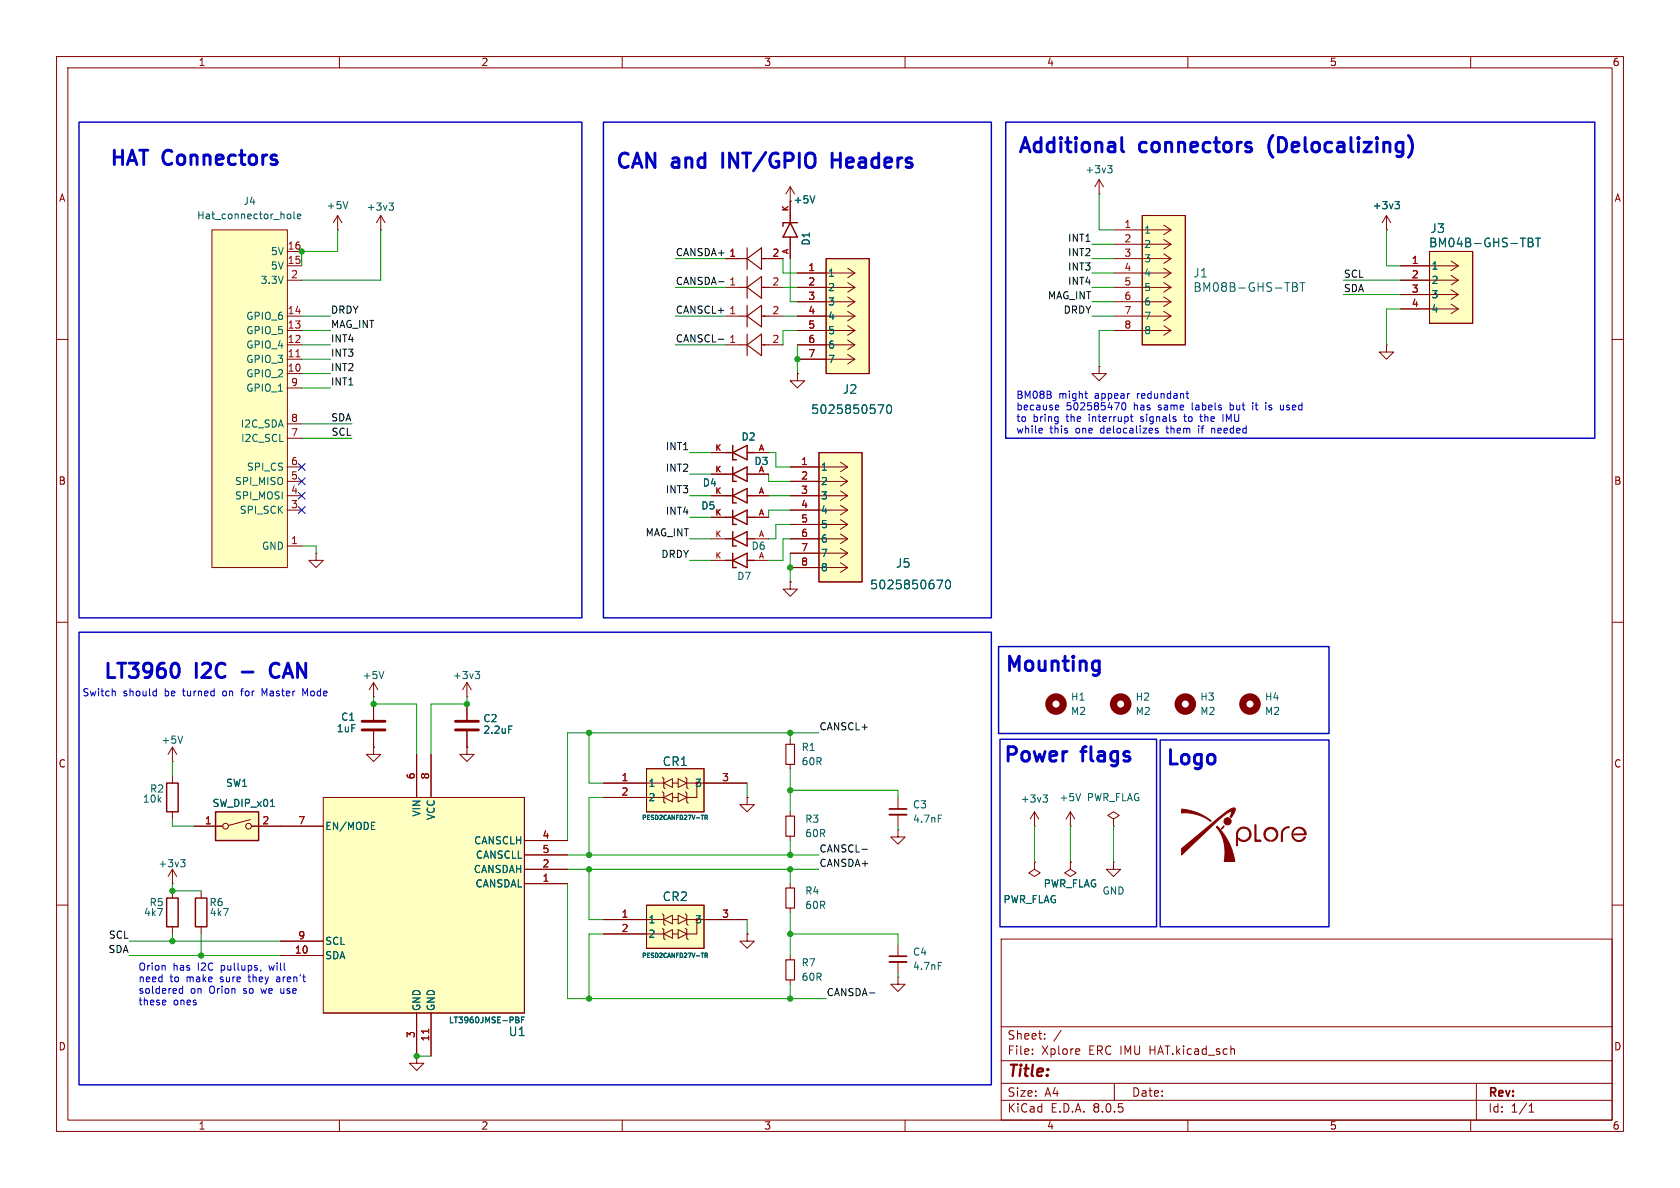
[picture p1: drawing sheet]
<svg xmlns="http://www.w3.org/2000/svg" width="297mm" height="210mm" viewBox="0 0 297 210" stroke-linecap="round" stroke-linejoin="round" font-family="sans-serif">
<defs><g id="words">
<g font-size="3.5" fill="#0000c2">
<text x="19.1" y="30">HAT Connectors</text>
<text x="179.8" y="27.2">Additional</text>
<text x="201.7" y="27.2">connectors</text>
<text x="225.4" y="27.2">(Delocalizing)</text>
<text x="108.5" y="30.5">CAN</text>
<text x="118.8" y="30.5">and</text>
<text x="128.7" y="30.5">INT/GPIO</text>
<text x="149" y="30.5">Headers</text>
<text x="177.5" y="118.9">Mounting</text>
<text x="18" y="120.7">LT3960</text>
<text x="34.6" y="120.7">I2C</text>
<text x="49.8" y="120.7">CAN</text>
<text x="177.3" y="134.9">Power</text>
<text x="191.5" y="134.9">flags</text>
<text x="206" y="135.4">Logo</text>
</g>
<text font-size="2.8" fill="#840000" x="178" y="190.9">Title:</text>
<g font-size="2.1" fill="#006464">
<text x="252.8" y="41.4">J3</text>
<text x="252.5" y="43.9">BM04B-GHS-TBT</text>
<text x="210.9" y="49.3">J1</text>
<text x="210.9" y="51.8">BM08B-GHS-TBT</text>
<text x="148.9" y="69.8">J2</text>
<text x="143.3" y="73.4">5025850570</text>
<text x="158.3" y="100.6">J5</text>
<text x="153.7" y="104.4">5025850670</text>
<text x="117.1" y="135.6">CR1</text>
<text x="117.1" y="159.5">CR2</text>
<text x="89.8" y="183.4">U1</text>
</g>
<g font-size="2.1" fill="#840000">
<text x="178" y="184">Sheet:</text>
<text x="178" y="186.7">File:</text>
<text x="184.1" y="186.7">Xplore</text>
<text x="192.5" y="186.7">ERC IMU</text>
<text x="203.5" y="186.7">HAT.kicad_sch</text>
<text x="178" y="196.9">KiCad</text>
<text x="178" y="194.1">Size:</text>
<text x="184.7" y="194.1">A4</text>
<text x="185.7" y="196.9">E.D.A.</text>
<text x="193.3" y="196.9">8.0.5</text>
<text x="200" y="194.1">Date:</text>
<text x="263" y="194.3">Rev:</text>
<text x="263" y="196.9">Id:</text>
<text x="267.1" y="196.9">1/1</text>
</g>
<g font-size="1.8" fill="#840000">
<text x="35" y="11.9">1</text>
<text x="85" y="11.9">2</text>
<text x="135" y="11.9">3</text>
<text x="185" y="11.9">4</text>
<text x="235" y="11.9">5</text>
<text x="285" y="11.9">6</text>
<text x="10.3" y="35.9">A</text>
<text x="285.3" y="35.9">A</text>
<text x="140.2" y="36.2">+5V</text>
<text x="10.3" y="85.9">B</text>
<text x="285.3" y="85.9">B</text>
<text x="10.3" y="135.9">C</text>
<text x="285.3" y="135.9">C</text>
<text x="10.3" y="185.9">D</text>
<text x="285.3" y="185.9">D</text>
<text x="35" y="199.9">1</text>
<text x="85" y="199.9">2</text>
<text x="135" y="199.9">3</text>
<text x="185" y="199.9">4</text>
<text x="235" y="199.9">5</text>
<text x="285" y="199.9">6</text>
</g>
<g font-size="1.8" fill="#006464">
<text x="191.8" y="30.8">+3v3</text>
<text x="34.7" y="39">Hat_connector_hole</text>
<text x="42.9" y="36.4">J4</text>
<text x="57.7" y="37.2">+5V</text>
<text x="64.7" y="37.4">+3v3</text>
<text x="202.2" y="41.5">1</text>
<text x="242.6" y="37.2">+3v3</text>
<text x="47.8" y="47.9">5V</text>
<text x="47.8" y="45.3">5V</text>
<text x="143.4" y="43.5" transform="rotate(-90 143.4 43.5)">D1</text>
<text x="202.2" y="44">2</text>
<text x="202.2" y="46.6">3</text>
<text x="253" y="47.9">1</text>
<text x="46" y="50.4">3.3V</text>
<text x="146.3" y="49.1">1</text>
<text x="146.3" y="51.7">2</text>
<text x="202.2" y="49.1">4</text>
<text x="202.2" y="51.7">5</text>
<text x="253" y="50.4">2</text>
<text x="253" y="52.9">3</text>
<text x="43.4" y="59.3">GPIO_5</text>
<text x="43.4" y="56.7">GPIO_6</text>
<text x="146.3" y="54.2">3</text>
<text x="146.3" y="56.7">4</text>
<text x="146.3" y="59.3">5</text>
<text x="202.2" y="54.2">6</text>
<text x="202.2" y="56.7">7</text>
<text x="202.2" y="59.3">8</text>
<text x="253" y="55.5">4</text>
<text x="43.4" y="64.4">GPIO_3</text>
<text x="43.4" y="61.8">GPIO_4</text>
<text x="146.3" y="61.8">6</text>
<text x="146.3" y="64.4">7</text>
<text x="43.4" y="66.9">GPIO_2</text>
<text x="43.4" y="69.4">GPIO_1</text>
<text x="42.5" y="75.8">I2C_SDA</text>
<text x="42.5" y="78.3">I2C_SCL</text>
<text x="43.6" y="83.4">SPI_CS</text>
<text x="131" y="78.1">D2</text>
<text x="133.3" y="82.4">D3</text>
<text x="145" y="83.4">1</text>
<text x="41.4" y="88.5">SPI_MOSI</text>
<text x="41.4" y="86">SPI_MISO</text>
<text x="124.1" y="86.2">D4</text>
<text x="145" y="86">2</text>
<text x="145" y="88.5">3</text>
<text x="42.3" y="91">SPI_SCK</text>
<text x="123.9" y="90.3">D5</text>
<text x="145" y="91">4</text>
<text x="145" y="93.6">5</text>
<text x="46.2" y="97.4">GND</text>
<text x="132.8" y="97.4">D6</text>
<text x="145" y="96.1">6</text>
<text x="145" y="98.7">7</text>
<text x="145" y="101.2">8</text>
<text x="130.2" y="102.7">D7</text>
<text x="64" y="120.2">+5V</text>
<text x="80" y="120.2">+3v3</text>
<text x="189.2" y="124.1">H1</text>
<text x="200.7" y="124.1">H2</text>
<text x="212.1" y="124.1">H3</text>
<text x="223.5" y="124.1">H4</text>
<text x="28.4" y="131.7">+5V</text>
<text x="59.4" y="129.6">1uF</text>
<text x="60.2" y="127.6">C1</text>
<text x="85.4" y="127.9">C2</text>
<text x="85.4" y="129.9">2.2uF</text>
<text x="189.2" y="126.6">M2</text>
<text x="200.7" y="126.6">M2</text>
<text x="212.1" y="126.6">M2</text>
<text x="223.5" y="126.6">M2</text>
<text x="141.6" y="132.9">R1</text>
<text x="141.6" y="135.5">60R</text>
<text x="25.2" y="142.1">10k</text>
<text x="26.4" y="140.3">R2</text>
<text x="37.5" y="142.8">SW_DIP_x01</text>
<text x="39.9" y="139.3">SW1</text>
<text x="114.6" y="139.3">1</text>
<text x="114.6" y="141.8">2</text>
<text x="122.8" y="139.3">3</text>
<text x="161.3" y="143.1">C3</text>
<text x="180.3" y="142.1">+3v3</text>
<text x="187.2" y="141.8">+5V</text>
<text x="192" y="141.8">PWR_FLAG</text>
<text x="57.4" y="146.9">EN/MODE</text>
<text x="74.5" y="144.5" transform="rotate(-90 74.5 144.5)">VIN</text>
<text x="77.1" y="145.1" transform="rotate(-90 77.1 145.1)">VCC</text>
<text x="83.7" y="149.5">CANSCLH</text>
<text x="142.2" y="145.6">R3</text>
<text x="142.2" y="148.2">60R</text>
<text x="161.3" y="145.6">4.7nF</text>
<text x="27.9" y="153.5">+3v3</text>
<text x="83.7" y="154.5">CANSDAH</text>
<text x="84" y="152">CANSCLL</text>
<text x="26.3" y="160.4">R5</text>
<text x="36.9" y="160.4">R6</text>
<text x="84" y="157.1">CANSDAL</text>
<text x="142.2" y="158.3">R4</text>
<text x="142.2" y="160.9">60R</text>
<text x="177.3" y="159.9">PWR_FLAG</text>
<text x="184.4" y="157.1">PWR_FLAG</text>
<text x="194.8" y="158.3">GND</text>
<text x="25.4" y="162.2">4k7</text>
<text x="37" y="162.2">4k7</text>
<text x="57.4" y="167.2">SCL</text>
<text x="114.6" y="163.4">1</text>
<text x="114.6" y="166">2</text>
<text x="122.8" y="163.4">3</text>
<text x="57.4" y="169.8">SDA</text>
<text x="141.6" y="171">R7</text>
<text x="141.6" y="173.6">60R</text>
<text x="161.3" y="169.1">C4</text>
<text x="161.3" y="171.7">4.7nF</text>
<text x="74.5" y="178.8" transform="rotate(-90 74.5 178.8)">GND</text>
<text x="77.1" y="178.8" transform="rotate(-90 77.1 178.8)">GND</text>
</g>
<g font-size="1.8" fill="#a90000">
<text x="198.7" y="40.4">1</text>
<text x="50.8" y="46.7">15</text>
<text x="50.8" y="44.2">16</text>
<text x="128.8" y="45.5">1</text>
<text x="136.5" y="45.5">2</text>
<text x="198.7" y="42.9">2</text>
<text x="198.7" y="45.5">3</text>
<text x="249.5" y="46.7">1</text>
<text x="51.4" y="49.3">2</text>
<text x="128.8" y="50.5">1</text>
<text x="136.5" y="50.5">2</text>
<text x="142.8" y="48">1</text>
<text x="142.8" y="50.5">2</text>
<text x="142.8" y="53.1">3</text>
<text x="198.7" y="48">4</text>
<text x="198.7" y="50.5">5</text>
<text x="198.7" y="53.1">6</text>
<text x="249.5" y="49.3">2</text>
<text x="249.5" y="51.8">3</text>
<text x="50.8" y="58.2">13</text>
<text x="50.8" y="55.6">14</text>
<text x="128.8" y="55.6">1</text>
<text x="136.5" y="55.6">2</text>
<text x="142.8" y="55.6">4</text>
<text x="142.8" y="58.2">5</text>
<text x="198.7" y="55.6">7</text>
<text x="198.7" y="58.2">8</text>
<text x="249.5" y="54.4">4</text>
<text x="50.8" y="65.8">10</text>
<text x="50.8" y="63.2">11</text>
<text x="50.8" y="60.7">12</text>
<text x="128.8" y="60.7">1</text>
<text x="136.5" y="60.7">2</text>
<text x="142.8" y="60.7">6</text>
<text x="142.8" y="63.2">7</text>
<text x="51.4" y="68.3">9</text>
<text x="51.4" y="77.2">7</text>
<text x="51.4" y="74.7">8</text>
<text x="51.4" y="82.3">6</text>
<text x="141.5" y="82.3">1</text>
<text x="51.4" y="89.9">3</text>
<text x="51.4" y="87.4">4</text>
<text x="51.4" y="84.8">5</text>
<text x="141.5" y="84.8">2</text>
<text x="141.5" y="87.4">3</text>
<text x="141.5" y="89.9">4</text>
<text x="141.5" y="92.5">5</text>
<text x="141.5" y="95">6</text>
<text x="51.4" y="96.3">1</text>
<text x="141.5" y="97.5">7</text>
<text x="141.5" y="100.1">8</text>
<text x="73.4" y="137.9" transform="rotate(-90 73.4 137.9)">6</text>
<text x="75.9" y="137.9" transform="rotate(-90 75.9 137.9)">8</text>
<text x="109.8" y="138.2">1</text>
<text x="109.8" y="140.7">2</text>
<text x="127.6" y="138.2">3</text>
<text x="36.1" y="145.8">1</text>
<text x="46.3" y="145.8">2</text>
<text x="52.6" y="145.8">7</text>
<text x="95.8" y="148.3">4</text>
<text x="95.8" y="156">1</text>
<text x="95.8" y="153.4">2</text>
<text x="95.8" y="150.9">5</text>
<text x="52.6" y="166.1">9</text>
<text x="109.8" y="162.3">1</text>
<text x="109.8" y="164.8">2</text>
<text x="127.6" y="162.3">3</text>
<text x="52" y="168.7">10</text>
<text x="73.4" y="183.6" transform="rotate(-90 73.4 183.6)">3</text>
<text x="75.9" y="184.2" transform="rotate(-90 75.9 184.2)">11</text>
</g>
<g font-size="1.8" fill="#0f0f0f">
<text x="119.4" y="45.4">CANSDA+ 1</text>
<text x="188.7" y="45.4">INT2</text>
<text x="188.7" y="47.9">INT3</text>
<text x="188.7" y="42.8">INT1</text>
<text x="119.4" y="50.5">CANSDA-</text>
<text x="185.2" y="53">MAG_INT</text>
<text x="188.7" y="50.5">INT4</text>
<text x="237.5" y="51.7">SDA</text>
<text x="237.5" y="49.2">SCL</text>
<text x="58.4" y="55.5">DRDY</text>
<text x="58.4" y="58.1">MAG_INT</text>
<text x="119.4" y="55.5">CANSCL+</text>
<text x="187.9" y="55.5">DRDY</text>
<text x="58.4" y="60.6">INT4</text>
<text x="58.4" y="63.2">INT3</text>
<text x="58.4" y="65.7">INT2</text>
<text x="119.4" y="60.6">CANSCL-</text>
<text x="58.4" y="68.2">INT1</text>
<text x="58.5" y="74.6">SDA</text>
<text x="58.5" y="77.1">SCL</text>
<text x="117.6" y="79.7">INT1</text>
<text x="117.6" y="83.5">INT2</text>
<text x="117.6" y="87.3">INT3</text>
<text x="114" y="94.9">MAG_INT</text>
<text x="117.6" y="91.1">INT4</text>
<text x="116.8" y="98.7">DRDY</text>
<text x="144.8" y="129.2">CANSCL+</text>
<text x="144.8" y="153.3">CANSDA+</text>
<text x="144.8" y="150.8">CANSCL-</text>
<text x="19.1" y="166">SCL</text>
<text x="19.1" y="168.6">SDA</text>
<text x="146" y="176.2">CANSDA-</text>
</g>
<g font-size="1.8" fill="#0000c2">
<text x="179.6" y="70.7">BM08B</text>
<text x="187.2" y="70.7">might</text>
<text x="193.7" y="70.7">appear</text>
<text x="201.3" y="70.7">redundant</text>
<text x="179.6" y="72.7">because</text>
<text x="179.6" y="74.8">to</text>
<text x="179.6" y="76.8">while</text>
<text x="182.6" y="74.8">bring</text>
<text x="185.6" y="76.8">this</text>
<text x="188.5" y="72.7">502585470</text>
<text x="188.6" y="74.8">the</text>
<text x="190.3" y="76.8">one</text>
<text x="192.8" y="74.8">interrupt</text>
<text x="194.8" y="76.8">delocalizes</text>
<text x="200.5" y="72.7">has</text>
<text x="202.1" y="74.8">signals</text>
<text x="205" y="72.7">same</text>
<text x="206.7" y="76.8">them</text>
<text x="210" y="74.8">to</text>
<text x="211.2" y="72.7">labels</text>
<text x="212.5" y="76.8">if</text>
<text x="213.1" y="74.8">the</text>
<text x="215" y="76.8">needed</text>
<text x="217.2" y="74.8">IMU</text>
<text x="218.1" y="72.7">but</text>
<text x="222.3" y="72.7">it</text>
<text x="224.8" y="72.7">is</text>
<text x="227.6" y="72.7">used</text>
<text x="14.5" y="123.3">Switch</text>
<text x="21.8" y="123.3">should</text>
<text x="29.2" y="123.3">be</text>
<text x="32.6" y="123.3">turned</text>
<text x="39.8" y="123.3">on</text>
<text x="43.3" y="123.3">for</text>
<text x="47.1" y="123.3">Master</text>
<text x="54.5" y="123.3">Mode</text>
<text x="24.4" y="171.8">Orion</text>
<text x="24.4" y="173.8">need</text>
<text x="30" y="173.8">to</text>
<text x="30.6" y="171.8">has</text>
<text x="33.1" y="173.8">make</text>
<text x="35.1" y="171.8">I2C</text>
<text x="39.2" y="173.8">sure</text>
<text x="39.3" y="171.8">pullups,</text>
<text x="44.4" y="173.8">they</text>
<text x="48.1" y="171.8">will</text>
<text x="49.5" y="173.8">aren't</text>
<text x="24.4" y="175.9">soldered</text>
<text x="24.4" y="177.9">these</text>
<text x="30.6" y="177.9">ones</text>
<text x="33.7" y="175.9">on</text>
<text x="37.1" y="175.9">Orion</text>
<text x="43.3" y="175.9">so</text>
<text x="46.7" y="175.9">we</text>
<text x="50.3" y="175.9">use</text>
</g>
<g font-size="1.4" fill="#a90000">
<text x="139.4" y="37.5" transform="rotate(-90 139.4 37.5)">K</text>
<text x="139.4" y="45" transform="rotate(-90 139.4 45)">A</text>
<text x="126.4" y="79.8">K</text>
<text x="126.4" y="83.6">K</text>
<text x="134.1" y="79.8">A</text>
<text x="134.1" y="83.6">A</text>
<text x="126.4" y="87.4">K</text>
<text x="134.1" y="87.4">A</text>
<text x="126.4" y="91.2">K</text>
<text x="126.4" y="95">K</text>
<text x="134.1" y="91.2">A</text>
<text x="134.1" y="95">A</text>
<text x="126.4" y="98.8">K</text>
<text x="134.1" y="98.8">A</text>
</g>
<text font-size="1.4" fill="#006464" x="79.3" y="181.1">LT3960JMSE-PBF</text>
<g font-size="1.1" fill="#006464">
<text x="113.4" y="145.1">PESD2CANFD27V-TR</text>
<text x="113.4" y="169.5">PESD2CANFD27V-TR</text>
</g>
</g></defs>
<g fill="none" stroke="#840000" stroke-width=".18">
<path d="M10 10h277v190h-277zM12 12h273v186h-273zM60 10v2M110 10v2M160 10v2M210 10v2M260 10v2M10 60h2M285 60h2M10 110h2M285 110h2M10 160h2"/>
<path d="M285 160h2M177 166h108v32h-108zM60 198v2M110 198v2M160 198v2M177 194.5h108M177 191.5h108M177 187.5h108M177 181.5h108M182.5 186.3v.1M182.5 185.5v.1M184.7 183.6v.1"/>
<path d="M184.7 182.8v.1M187.6 182.1l-1.3 2M190.7 185.4l.2 .4-.7 .1M190.8 186.3l-.1 .1M197 191.5v3M210 198v2M218 185.4l.2 .2v.8M260 198v2M261 191.5v6.5M270.3 196.6h.9M270.3 195.5l.4-.4v1.5"/>
</g>
<path d="M38.1 143.5h7.6v5.1h-7.6z" fill="#ffffc2"/>
<g fill="none" stroke="#840000" stroke-width=".18">
<path d="M125.7 87.6h2.6M125.7 91.4h2.6M133.3 87.6h2.6M133.3 91.4h2.6M82.5 123.2h.1M82.5 120.7l-.7 1.2M82.5 120.7v2.5M82.5 120.7l.8 1.2M30.5 157.5v1.3M34.3 146.1h5.1M35.6 157.5v1.3M44.3 144.9l-3.9 1"/>
<path d="M44.4 146.1h5.1M189.2 152.4v1.3l1 .6-1 .6-1-.6 1-.6M189.2 152.4h.1M30.5 163.8v1.3M35.6 163.8v1.3"/>
<circle cx="39.9" cy="146.1" r=".51"/>
<circle cx="43.9" cy="146.1" r=".51"/>
</g>
<path d="M128.3 87.6h1.2M128.3 91.4h1.2M129.5 87.6l2.6-1.2v2.5zM129.5 91.4l2.6-1.2v2.5zM129.5 86.4v2.5h.7M129.5 90.2v2.5h.7M132.1 87.6h1.2M132.1 91.4h1.2M29.5 158.8h2v5h-2zM34.5 158.8h2.1v5h-2.1zM38.1 143.5h7.6v5.1h-7.6z" fill="none" stroke="#840000" stroke-width=".25"/>
<path d="M84 118.7h.8l-.4 .5 .3 .1 .1 .4-.3 .3h-.3M47.8 142.6h.7" fill="none" stroke="#006464" stroke-width=".18"/>
<circle cx="198.1" cy="124.5" r="1.27" fill="none" stroke="#840000" stroke-width="1.3"/>
<path d="M37.5 40.6h13.3v59.7h-13.3z" fill="#ffffc2"/>
<g fill="none" stroke="#840000" stroke-width=".18">
<path d="M59.7 38.1l-.8 1.3M59.7 38.1v2.5M59.7 38.1l.8 1.3M67.3 38.1l-.8 1.3M67.3 38.1v2.5M67.3 38.1l.8 1.3M37.5 40.6h13.3v59.7h-13.3zM50.8 58.4h2.5M50.8 55.9h2.5M50.8 47h2.5M50.8 44.5h2.5M50.8 49.5h2.5"/>
<path d="M59.7 40.6h.1M67.3 40.6h.1M50.8 66h2.5M50.8 63.5h2.5M50.8 61h2.5M50.8 77.5h2.5M50.8 74.9h2.5M50.8 68.6h2.5M245.1 61v1.2h1.3l-1.3 1.3-1.3-1.3h1.3M245.1 61h.1M50.8 96.5h2.5M50.8 90.2h2.5"/>
<path d="M50.8 87.6h2.5M50.8 85.1h2.5M50.8 82.6h2.5M55.9 97.8v1.3h1.2l-1.2 1.2-1.3-1.2h1.3M55.9 97.8h.1M66 132.1v1.3h1.3l-1.3 1.2-1.2-1.2h1.2M66 132.1h.1M66 124.5v2.8M66 129.3v2.8M82.5 132.1v1.3h1.3l-1.3 1.2-1.2-1.2h1.2M82.5 132.1h.1M82.5 124.5v2.8"/>
<path d="M82.5 129.3v2.8M139.7 130.8v.8M139.7 135.1v.8M132.1 141v1.2h1.2l-1.2 1.3-1.3-1.3h1.3M132.1 141h.1M139.7 143.5v.8M139.7 147.8v.8M139.7 156.2v.8M158.7 146.7v1.3h1.3l-1.3 1.2-1.2-1.2h1.2M158.7 146.7h.1M158.7 141v2M158.7 144v2.1"/>
<path d="M182.9 152.4v1.3l1 .6-1 .6-1-.6 1-.6M182.9 152.4h.1M182.9 146.1h.1M182.9 143.5l-.8 1.3M182.9 143.5v2.6M182.9 143.5l.7 1.3M189.2 146.1h.1M189.2 143.5l-.7 1.3M189.2 143.5v2.6M189.2 143.5l.8 1.3M196.8 152.4v1.3h1.3l-1.3 1.2-1.2-1.2h1.2M196.8 152.4h.1"/>
<path d="M196.8 144.8l1.1-.7-1.1-.6-1 .6 1 .7v1.3M196.8 146.1h.1M139.7 160.5v.8M158.7 167v2M158.7 170.1v2M73.7 186.7v1.3h1.2l-1.2 1.2-1.3-1.2h1.3M73.7 186.7h.1"/>
</g>
<path d="M52.3 63.1h.7" fill="none" stroke="#a90000" stroke-width=".18"/>
<path d="M51 37.8l.3 .1 .1 .2v.5l-.4 .1M52 37.4v1.1l.1 .2M52.6 38.3l.6-.2-.1-.2-.3-.1-.2 .2v.6h.5M61.5 35.6l-.4 1.3M68.8 35.9h.7l-.4 .5 .4 .1v.4l-.2 .3h-.4M89.9 128.3h.6M165.9 144.1h.6M184.4 140.5h.8l-.5 .5 .4 .1 .1 .5-.3 .2h-.3M191 140.3l-.4 1.2M165.9 170.1h.6" fill="none" stroke="#006464" stroke-width=".18"/>
<g fill="none" stroke="#840000" stroke-width="1.3">
<circle cx="186.7" cy="124.5" r="1.27"/>
<circle cx="209.5" cy="124.5" r="1.27"/>
<circle cx="221" cy="124.5" r="1.27"/>
</g>
<path d="M64 129h4.1M64 127.5h4.1M80.5 129h4.1M80.5 127.5h4.1" fill="none" stroke="#840000" stroke-width=".51"/>
<g fill="#840000" stroke="#840000" stroke-width=".18">
<path d="M221.8 145.8h.2l.1 2.7h.8v.2h-1z"/>
<path d="M216.3 146l.1 .1-.4 .5-.1-.1z"/>
<path d="M226.9 146.5l.6-.3 .4-.1v.2a1.32 1.32 0 0 0-1.2 1.7v.7h-.2v-.9a1.67 1.67 0 0 1 .4-1.3z"/>
<path d="M215.2 146.1a11.4 11.4 0 0 1 3.1 6.2h-1.9l.1-.2a7.3 7.3 0 0 0-1.5-5.9z"/>
<path d="M208.9 143h.2a9.5 9.5 0 0 1 5 2.1l-.1 .1a7.2 7.2 0 0 0-5.1-1.5z"/>
<path d="M219 146.6a1.28 1.28 0 0 1 1.8 0 1.28 1.28 0 0 1 0 1.8 1.28 1.28 0 0 1-1.8 0v-.3l.2 .2a1.07 1.07 0 0 0 1.6-.3 1.07 1.07 0 0 0-.6-1.5 1.07 1.07 0 0 0-1.4 .9v2.1h-.2v-1.7a1.46 1.46 0 0 1 .4-1.2z"/>
<path d="M223.8 146.6l.8-.4a1.24 1.24 0 0 1 1.3 1.2 1.24 1.24 0 0 1-1.1 1.3v-.2a1.02 1.02 0 0 0 .8-1.5 1.02 1.02 0 0 0-1.7 0 1.02 1.02 0 0 0 .6 1.5v.2a1.24 1.24 0 0 1-1-.8 1.24 1.24 0 0 1 .3-1.3z"/>
<path d="M208.9 150l6.9-5.7 1.7-1.2a.56 .56 0 0 1 .9 0l-.6 1.2a.17 .17 0 0 1-.2 .2 .17 .17 0 0 1-.1-.3l.2-.5a.18 .18 0 0 0 0-.3 .18 .18 0 0 0-.3 .1l-2 1.5-6.5 6.1z"/>
<path d="M228.7 146.6a1.26 1.26 0 0 1 1.5-.3 1.26 1.26 0 0 1 .7 1.3h-2.1l-.1-.2h2a1.06 1.06 0 0 0-1.6-.8 1.06 1.06 0 0 0-.3 1.7 1.06 1.06 0 0 0 1.7-.3h.3a1.26 1.26 0 0 1-1.9 .6 1.26 1.26 0 0 1-.2-2z"/>
<circle cx="217" cy="145.2" r=".63"/>
</g>
<path d="M138.9 131.6h1.6v3.5h-1.6zM138.9 144.3h1.6v3.5h-1.6zM138.9 157h1.6v3.5h-1.6z" fill="none" stroke="#840000" stroke-width=".2"/>
<path d="M157.2 144h3.1M157.2 170.1h3.1" fill="none" stroke="#840000" stroke-width=".33"/>
<path d="M157.2 143h3.1M157.2 169h3.1" fill="none" stroke="#840000" stroke-width=".3"/>
<path d="M252.7 44.5v12.7h7.6v-12.7" fill="none" stroke="#ffffc2" stroke-width=".18"/>
<path d="M252.7 44.5h7.6v12.7h-7.6z" fill="#ffffc2"/>
<g fill="none" stroke="#840000" stroke-width=".18">
<path d="M194.3 34.3h.1M194.3 31.8l-.8 1.2M194.3 31.8v2.5M194.3 31.8l.8 1.2M245.1 38.1l-.8 1.3M245.1 38.1v2.5M245.1 38.1l.8 1.3M245.1 40.6h.1M247.6 54.6h10.2M247.6 52.1h10.2M247.6 49.5h10.2M247.6 47h10.2"/>
<path d="M252.7 44.5h7.6v12.7h-7.6zM256.5 53.8l1.3 .8M256.5 51.2l1.3 .9M256.5 48.7l1.3 .8M256.5 46.1l1.3 .9M257.8 54.6l-1.3 .9M257.8 52.1l-1.3 .8M257.8 49.5l-1.3 .9M257.8 47l-1.3 .8M194.3 64.8v1.2h1.3l-1.3 1.3-1.3-1.3h1.3M194.3 64.8h.1"/>
</g>
<path d="M195.8 29.3h.8l-.4 .5 .3 .1 .1 .4-.2 .3h-.4M246.6 35.6h.8l-.4 .5 .3 .1 .1 .5-.2 .2h-.4M270.2 42.1h.5l.2 .1 .1 .3-.3 .3M270.2 42.8h.5M270.7 42.8a.41 .41 0 0 1 .4 .4 .41 .41 0 0 1-.3 .4h-.6M271.5 42.1h.8M271.9 42.1v1.5" fill="none" stroke="#006464" stroke-width=".18"/>
<path d="M209.5 38.1v22.9h-7.6" fill="none" stroke="#ffffc2" stroke-width=".18"/>
<path d="M201.9 38.1h7.6v22.9h-7.6z" fill="#ffffc2"/>
<g fill="none" stroke="#840000" stroke-width=".18">
<path d="M201.9 38.1h7.6v22.9h-7.6zM205.7 39.8l1.3 .8M196.8 58.4h10.2M196.8 55.9h10.2M196.8 53.3h10.2M196.8 50.8h10.2M196.8 48.3h10.2M196.8 45.7h10.2M196.8 43.2h10.2M196.8 40.6h10.2M205.7 57.6l1.3 .8M205.7 55l1.3 .9"/>
<path d="M205.7 52.5l1.3 .8M205.7 50l1.3 .8M205.7 47.4l1.3 .9M205.7 44.9l1.3 .8M205.7 42.3l1.3 .9M207 58.4l-1.3 .9M207 55.9l-1.3 .8M207 53.3l-1.3 .9M207 50.8l-1.3 .8M207 48.3l-1.3 .8M207 45.7l-1.3 .9M207 43.2l-1.3 .8"/>
<path d="M207 40.6l-1.3 .9M141 66v1.3h1.2l-1.2 1.3-1.3-1.3h1.3M141 66h.1"/>
</g>
<path d="M228.5 50h.5l.2 .1 .1 .3-.3 .3M228.5 50.7h.5M229 50.7a.41 .41 0 0 1 .4 .4 .41 .41 0 0 1-.3 .4h-.6M229.8 50h.9M230.3 50v1.5" fill="none" stroke="#006464" stroke-width=".18"/>
<path d="M153.7 45.7v20.3" fill="none" stroke="#ffffc2" stroke-width=".18"/>
<path d="M146 45.7h7.7v20.3h-7.7z" fill="#ffffc2"/>
<g fill="none" stroke="#840000" stroke-width=".18">
<path d="M139.7 33l-.8 1.3M139.7 33v5.1M139.7 33l.8 1.3M128.3 55.9h2.5M128.3 50.8h2.5M128.3 45.7h2.5M135.9 55.9h2.5M135.9 50.8h2.5M135.9 45.7h2.5M139.7 43.2v2.5M141 58.4h10.1M141 55.9h10.1"/>
<path d="M141 53.3h10.1M141 50.8h10.1M141 48.3h10.1M146 45.7h7.7v20.3h-7.7zM149.9 57.6l1.2 .8M149.9 55l1.2 .9M149.9 52.5l1.2 .8M149.9 50l1.2 .8M149.9 47.4l1.2 .9M151.1 58.4l-1.2 .9M151.1 55.9l-1.2 .8M151.1 53.3l-1.2 .9"/>
<path d="M151.1 50.8l-1.2 .8M151.1 48.3l-1.2 .8M128.3 61h2.5M135.9 61h2.5M141 63.5h10.1M141 61h10.1M149.9 62.7l1.2 .8M149.9 60.1l1.2 .9M151.1 63.5l-1.2 .8M151.1 61l-1.2 .8M139.7 168.9v.8M139.7 173.2v.8"/>
<path d="M158.7 172.7v1.3h1.3l-1.3 1.3-1.2-1.3h1.2M158.7 172.7h.1"/>
</g>
<path d="M144.1 34.6l-.5 1.3M155.2 71.6h1l-.6 1.5M157 71.6h.1a.83 .83 0 0 1 .6 .6 .83 .83 0 0 1-.3 .8l-.1 .1a.83 .83 0 0 1-.6-.6 .83 .83 0 0 1 .3-.9z" fill="none" stroke="#006464" stroke-width=".18"/>
<path d="M139.7 38.1v1.3M139.7 39.4l1.3 2.5h-2.6zM141 39.4h-2.6v.6M139.7 41.9v1.3" fill="none" stroke="#840000" stroke-width=".25"/>
<g fill="none" stroke="#840000" stroke-width=".2">
<path d="M130.8 45.7h1.3M130.8 50.8h1.3M130.8 55.9h1.3M132.1 45.7l2.5-1.9v3.8zM132.1 50.8l2.5-1.9v3.8zM132.1 55.9l2.5-1.9v3.8zM132.1 43.8v3.8M132.1 48.9v3.8M132.1 54v3.8M132.1 59.1v3.8M134.6 45.7h1.3M134.6 50.8h1.3"/>
<path d="M134.6 55.9h1.3M130.8 61h1.3M132.1 61l2.5-1.9v3.8zM134.6 61h1.3M138.9 169.7h1.6v3.5h-1.6z"/>
</g>
<path d="M114.3 160h10.2v7.6h-10.2z" fill="none" stroke="#ffffc2" stroke-width=".18"/>
<path d="M114.3 160h10.2v7.6h-10.2z" fill="#ffffc2"/>
<g fill="none" stroke="#840000" stroke-width=".18">
<path d="M125.7 80h2.6M125.7 83.8h2.6M125.7 95.3h2.6M133.3 80h2.6M133.3 83.8h2.6M133.3 95.3h2.6M106.7 165.1h10.6M106.7 162.6h10.6M114.3 160h10.2v7.6h-10.2zM117.1 161.5l.2 .3v1.5l.3 .3M117.1 164.1l.2 .2v1.6l.3 .2M117.3 165.1l1.6-.8v1.6z"/>
<path d="M117.3 162.6l1.6-.8v1.5zM118.9 165.1h1M118.9 162.6h1M119.9 164.3l1.5 .8-1.5 .8zM119.9 161.8l1.5 .8-1.5 .7zM121.2 164.1l.2 .2v1.6l.3 .2M121.2 161.5l.2 .3v1.5l.3 .3M121.4 162.6h10.7M123.2 162.6v2.5h-1.8M132.1 165.1v1.3h1.2l-1.2 1.2-1.3-1.2h1.3M132.1 165.1h.1"/>
</g>
<path d="M124.6 168.9h.4v-.3l-.4-.1v.8M124.8 168.9l.3 .4" fill="none" stroke="#006464" stroke-width=".18"/>
<path d="M129.5 78.7v2.6h.7M128.3 80h1.2M128.3 83.8h1.2M128.3 95.3h1.2M129.5 80l2.6-1.3v2.6zM129.5 83.8l2.6-1.2v2.5zM129.5 95.3l2.6-1.3v2.5zM129.5 82.6v2.5h.7M129.5 94v2.5h.7M132.1 80h1.2M132.1 83.8h1.2M132.1 95.3h1.2" fill="none" stroke="#840000" stroke-width=".25"/>
<path d="M114.3 135.9h10.2v7.6h-10.2z" fill="none" stroke="#ffffc2" stroke-width=".18"/>
<path d="M114.3 135.9h10.2v7.6h-10.2z" fill="#ffffc2"/>
<g fill="none" stroke="#840000" stroke-width=".18">
<path d="M125.7 99.1h2.6M133.3 99.1h2.6M139.7 102.9v1.2h1.3l-1.3 1.3-1.3-1.3h1.3M139.7 102.9h.1M30.5 134.6h.1M30.5 132.1l-.8 1.3M30.5 132.1v2.5M30.5 137.2v1.2M30.5 132.1l.7 1.3M66 123.2h.1M66 120.7l-.7 1.2M66 120.7v2.5"/>
<path d="M66 120.7l.8 1.2M106.7 138.4h10.6M114.3 135.9h10.2v7.6h-10.2zM117.1 137.4l.2 .3v1.5l.3 .2M117.1 140l.2 .2v1.5l.3 .3M117.3 138.4l1.6-.7v1.5zM118.9 138.4h1M119.9 137.7l1.5 .7-1.5 .8zM121.2 140l.2 .2v1.5l.3 .3M121.2 137.4l.2 .3v1.5l.3 .2M121.4 138.4h10.7M123.2 138.4v2.6h-1.8"/>
<path d="M30.5 143.5v1.3M106.7 141h10.6M117.3 141l1.6-.8v1.5zM118.9 141h1M119.9 140.2l1.5 .8-1.5 .7z"/>
</g>
<path d="M67.9 118.7l-.5 1.3M32.3 130.1l-.4 1.3M124.6 144.5h.4v-.3l-.4-.1v.8M124.8 144.5l.3 .4" fill="none" stroke="#006464" stroke-width=".18"/>
<path d="M128.3 99.1h1.2M129.5 99.1l2.6-1.3v2.5zM129.5 97.8v2.5h.7M132.1 99.1h1.2M29.5 138.4h2v5.1h-2z" fill="none" stroke="#840000" stroke-width=".25"/>
<path d="M152.4 80v22.9h-7.6" fill="none" stroke="#ffffc2" stroke-width=".18"/>
<path d="M144.8 80h7.6v22.9h-7.6z" fill="#ffffc2"/>
<g fill="none" stroke="#840000" stroke-width=".18">
<path d="M139.7 97.8h10.2M139.7 95.3h10.2M139.7 92.7h10.2M139.7 90.2h10.2M139.7 87.6h10.2M139.7 85.1h10.2M139.7 82.6h10.2M144.8 80h7.6v22.9h-7.6zM148.6 99.5l1.3 .8M148.6 96.9l1.3 .9M148.6 94.4l1.3 .9M148.6 91.9l1.3 .8"/>
<path d="M148.6 89.3l1.3 .9M148.6 86.8l1.3 .8M148.6 84.2l1.3 .9M148.6 81.7l1.3 .9M149.9 97.8l-1.3 .8M149.9 95.3l-1.3 .8M149.9 92.7l-1.3 .9M149.9 90.2l-1.3 .8M149.9 87.6l-1.3 .9M149.9 85.1l-1.3 .8M149.9 82.6l-1.3 .8M139.7 100.3h10.2"/>
<path d="M149.9 100.3l-1.3 .9M30.5 156.2h.1M30.5 153.7l-.8 1.2M30.5 153.7v2.5M30.5 153.7l.7 1.2"/>
</g>
<path d="M165.6 102.6h1l-.6 1.5M167.4 102.6h.1a.83 .83 0 0 1 .6 .6 .83 .83 0 0 1-.3 .8l-.1 .1a.83 .83 0 0 1-.6-.7 .83 .83 0 0 1 .3-.8zM31.9 152h.8l-.4 .4 .4 .2v.4l-.2 .2h-.4" fill="none" stroke="#006464" stroke-width=".18"/>
<path d="M92.7 141v38.1h-35.6" fill="none" stroke="#ffffc2" stroke-width=".18"/>
<path d="M57.1 141h35.6v38.1h-35.6z" fill="#ffffc2"/>
<g fill="none" stroke="#840000" stroke-width=".18">
<path d="M139.7 35.6v2.5M128.3 45.7h2.5M135.9 45.7h2.5M139.7 43.2v2.5M141 48.3h5M141 50.8h5M141 53.3h5M141 55.9h5M141 58.4h5M245.1 40.6h.1M247.6 47h5.1M247.6 49.5h5.1"/>
<path d="M247.6 52.1h5.1M247.6 54.6h5.1M141 66h.1M141 61h5M141 63.5h5M125.7 87.6h2.6M125.7 91.4h2.6M125.7 83.8h2.6M125.7 80h2.6M133.3 87.6h2.6M133.3 91.4h2.6M133.3 83.8h2.6"/>
<path d="M133.3 80h2.6M139.7 82.6h5.1M139.7 85.1h5.1M139.7 87.6h5.1M139.7 90.2h5.1M139.7 92.7h5.1M139.7 95.3h5.1M139.7 97.8h5.1M139.7 102.9h.1M139.7 100.3h5.1M66 132.1h.1M66 124.5v2.8"/>
<path d="M66 129.3v2.8M73.7 133.4v7.6M76.2 133.4v7.6M82.5 132.1h.1M82.5 124.5v2.8M82.5 129.3v2.8M106.7 138.4h7.6M124.5 138.4h7.6M34.3 146.1h5.1M44.4 146.1h12.7M57.1 141h35.6v38.1h-35.6zM92.7 141v38.1h-35.6"/>
<path d="M92.7 156.2h7.6M92.7 153.7h7.6M92.7 148.6h7.6M92.7 151.1h7.6M106.7 141h7.6M132.1 141h.1M182.9 152.4h.1M189.2 152.4h.1M49.5 168.9h7.6M49.5 166.4h7.6M73.7 179.1v7.6M76.2 179.1v7.6"/>
<path d="M106.7 162.6h7.6M106.7 165.1h7.6M124.5 162.6h7.6M132.1 165.1h.1M73.7 186.7h.1"/>
</g>
<path d="M75.8 181.9v.7" fill="none" stroke="#a90000" stroke-width=".18"/>
<g fill="none" stroke="#006464" stroke-width=".18">
<path d="M144.1 34.6l-.5 1.3M246.6 35.6h.8l-.4 .5 .3 .1 .1 .5-.2 .2h-.4M270.2 42.1h.5l.2 .1 .1 .3-.3 .3M270.2 42.8h.5M270.7 42.8a.41 .41 0 0 1 .4 .4 .41 .41 0 0 1-.3 .4h-.6M271.5 42.1h.8M271.9 42.1v1.5M155.2 71.6h1l-.6 1.5M157 71.6h.1a.83 .83 0 0 1 .6 .6 .83 .83 0 0 1-.3 .8l-.1 .1a.83 .83 0 0 1-.6-.6 .83 .83 0 0 1 .3-.9zM165.6 102.6h1l-.6 1.5M167.4 102.6h.1a.83 .83 0 0 1 .6 .6 .83 .83 0 0 1-.3 .8l-.1 .1a.83 .83 0 0 1-.6-.7 .83 .83 0 0 1 .3-.8zM89.9 128.3h.6"/>
<path d="M47.8 142.6h.7M65.7 146.6h.6M65.7 145.4h.6M124.6 144.5h.4v-.3l-.4-.1v.8M124.8 144.5l.3 .4M91.2 179.8l.5 .1v.2l-.2 .2M92.7 179.8h-.5v1M124.6 168.9h.4v-.3l-.4-.1v.8M124.8 168.9l.3 .4M91.2 180.3h.3M91.5 180.3l.3 .2-.1 .2-.5 .1M92.2 180.3h.3"/>
</g>
<path d="M127 60h.9M127 49.8h1M152.4 150.1h.9M153.7 175.5h1" fill="none" stroke="#0f0f0f" stroke-width=".18"/>
<path d="M147.1 27.1v2.5M147.1 28.3h1.5M198.3 24.3v2.2l.4 .3M249.5 24.7a3 3 0 0 1 0 2.4M31.1 117.2a1.49 1.49 0 0 1 .5 2.1l-.5 .5M42.8 118.8h1.9M48.9 117.2a1.32 1.32 0 0 0-.9 2.2l.2 .2 .7 .2" fill="none" stroke="#0000c2" stroke-width=".51"/>
<g fill="none" stroke="#0000c2" stroke-width=".18">
<path d="M184.2 76.5h-.1M184.2 75.8l.1 .2-.6 .1M187.1 72.4l-.3 .1M187.1 71.7l.1 .2-.6 .1M191.8 69.6h.5M192 70.4h.3M198.3 71.7l.1 .5 .2 .3 .3-.2 .1-.6M199.8 73.7h.5M200 73.2v1.1l.3 .2M204.3 75.8v.3l.4 .1 .1 .2-.2 .1h-.4M209.3 73.7h.4M209.4 73.2l.1 1.2"/>
<path d="M209.7 69.6h.5M209.9 69.1v1.1l.3 .2M211.9 75.7v.8M212.1 73.7h.5M212.3 73.2v1.1l.3 .2M214.2 75.7v.8M214.6 75.7l-.4 .1M216.2 73.2v1.3M217.5 71.2v1.3M217.5 72.4l.1 .1M217.6 71.6l-.1 .1M221.5 71.2v.1"/>
<path d="M221.5 71.6v.9M223.8 71.2v.1M223.8 71.6v.9M226.9 72.3l-.4 .2M226.9 71.6v.9M20 122.2l.4 .1v.7M27.3 122.2h.3M27.6 121.7v1.3M27.6 123h-.3M42.5 122.2h.5M42.8 121.8l-.1 1.2M46.8 122.6l-.5-.9v1.3"/>
<path d="M54.4 121.7l-.4 .9-.5-.9v1.3M29.1 176.8l.2 .3-.6 .1M29.3 177.6h-.2M31.7 175.4l.2 .2 .4-.1M32.3 174.3v1.3M32.3 174.8l-.4-.1-.2 .3M46.1 171.4l-.1 .3M49 172.7l-.1 .1M49 173.1l-.1 .1 .1 .4M49.6 174.7v.7l.2 .2"/>
</g>
<path d="M14 21.6h88.9v87.6h-88.9zM106.7 21.6h68.6v87.6h-68.6zM177.8 21.6h104.1v55.9h-104.1zM14 111.8h161.3v80h-161.3zM176.5 114.3h58.4v15.4h-58.4zM176.8 130.7h27.7v33.1h-27.7zM205.1 130.8h29.8v33h-29.8z" fill="none" stroke="#0000c2" stroke-width=".25"/>
<g fill="none" stroke="#009600" stroke-width=".18">
<path d="M194.3 34.3v6.3h2.5M53.3 58.4h5.1M53.3 55.9h5.1M59.7 40.6v3.9h-6.4v2.5M67.3 40.6v8.9h-14M119.4 55.9h8.9M119.4 50.8h8.9M119.4 45.7h8.9M138.4 55.9h2.6M138.4 45.7v2.6h2.6M138.4 50.8h2.6M139.7 45.7v7.6h1.3"/>
<path d="M141 58.4h-2.6v2.6M193 55.9h3.8M193 50.8h3.8M193 53.3h3.8M193 48.3h3.8M193 45.7h3.8M193 43.2h3.8M196.8 58.4h-2.5v6.4M237.5 49.5h10.1M237.5 52.1h10.1M245.1 40.6v6.4h2.5M247.6 54.6h-2.5v6.4"/>
<path d="M53.3 61h5.1M53.3 66h5.1M53.3 68.6h5.1M53.3 63.5h5.1M53.3 74.9h8.9M53.3 77.5h8.9M119.4 61h8.9M141 61v5M53.3 96.5h2.6v1.3M121.9 99.1h3.8M121.9 83.8h3.8M121.9 80h3.8"/>
<path d="M121.9 87.6h3.8M121.9 95.3h3.8M121.9 91.4h3.8M135.9 80h1.3v2.6h2.5M135.9 87.6h3.8M135.9 83.8v1.3h3.8M139.7 97.8v5.1M139.7 95.3h-1.3v3.8h-2.5M139.7 92.7h-2.5v2.6h-1.3M139.7 90.2h-3.8v1.2M30.5 134.6v2.6M66 123.2v1.3h7.7v8.9"/>
<path d="M82.5 123.2v1.3h-6.3v8.9M104.1 129.5v8.9h2.6M132.1 138.4v2.6M139.7 129.5v1.3M139.7 135.9v7.6M139.7 139.7h19v1.3M144.8 129.5h-44.5v19.1M30.5 144.8v1.3h3.8M30.5 156.2v1.3h5.1M100.3 151.1h44.5M100.3 153.7h44.5M100.3 156.2v20.3h45.7"/>
<path d="M104.1 153.7v8.9h2.6M106.7 141h-2.6v10.1M139.7 148.6v2.5M139.7 153.7v2.5M158.7 146.1v.6M182.9 146.1v6.3M189.2 146.1v6.3M196.8 146.1v6.3M22.9 168.9h26.6M22.9 166.4h26.6M30.5 165.1v1.3M35.6 165.1v3.8"/>
<path d="M106.7 165.1h-2.6v11.4M132.1 162.6v2.5M139.7 161.3v7.6M139.7 174v2.5M139.7 165.1h19v1.9M158.7 172.1v.6M73.7 186.7h2.5"/>
</g>
<path d="M52.7 89.6l1.2 1.2M52.7 87l1.2 1.2M52.7 81.9l1.2 1.3M52.7 84.5l1.2 1.2M53.9 89.6l-1.2 1.2M53.9 87l-1.2 1.2M53.9 81.9l-1.2 1.3M53.9 84.5l-1.2 1.2" fill="none" stroke="#000084" stroke-width=".18"/>
<g fill="#009600" stroke="#009600" stroke-width=".18">
<circle cx="53.3" cy="44.5" r=".46"/>
<circle cx="139.7" cy="153.7" r=".46"/>
<circle cx="139.7" cy="139.7" r=".46"/>
<circle cx="139.7" cy="165.1" r=".46"/>
<circle cx="104.1" cy="151.1" r=".46"/>
<circle cx="104.1" cy="129.5" r=".46"/>
<circle cx="30.5" cy="157.5" r=".46"/>
<circle cx="35.6" cy="168.9" r=".46"/>
<circle cx="30.5" cy="166.4" r=".46"/>
<circle cx="66" cy="124.5" r=".46"/>
<circle cx="139.7" cy="151.1" r=".46"/>
<circle cx="139.7" cy="129.5" r=".46"/>
<circle cx="104.1" cy="176.5" r=".46"/>
<circle cx="73.7" cy="186.7" r=".46"/>
<circle cx="104.1" cy="153.7" r=".46"/>
<circle cx="82.5" cy="124.5" r=".46"/>
<circle cx="139.7" cy="176.5" r=".46"/>
<circle cx="139.7" cy="100.3" r=".46"/>
<circle cx="141" cy="63.5" r=".46"/>
</g>
<use href="#words"/>
</svg>
